One B-rep face of a CAD part: STEP entity #451.
In plain terms, the planar face has unit normal (1, 0, 0).
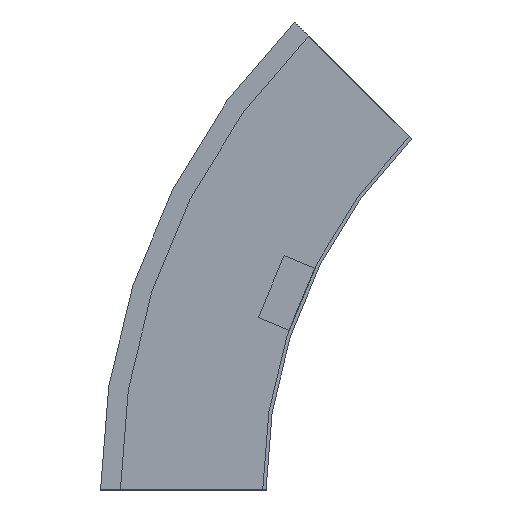
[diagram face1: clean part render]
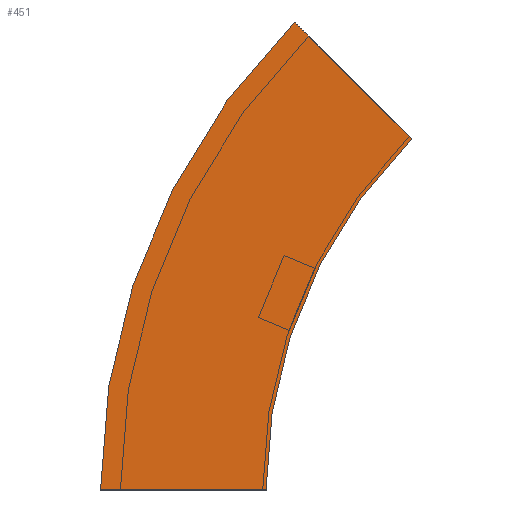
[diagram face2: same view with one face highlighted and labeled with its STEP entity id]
Its self-contained STEP definition (entity closure, numbers rounded to 3 decimals):
#3 = DIRECTION ( 'NONE',  ( 0., 0.707, 0.707 ) ) ;
#33 = CARTESIAN_POINT ( 'NONE',  ( 0., 100., 0. ) ) ;
#54 = LINE ( 'NONE', #233, #294 ) ;
#59 = ORIENTED_EDGE ( 'NONE', *, *, #468, .F. ) ;
#76 = AXIS2_PLACEMENT_3D ( 'NONE', #216, #171, #168 ) ;
#104 = ORIENTED_EDGE ( 'NONE', *, *, #415, .T. ) ;
#110 = AXIS2_PLACEMENT_3D ( 'NONE', #204, #162, #329 ) ;
#139 = CARTESIAN_POINT ( 'NONE',  ( 0., 0., 0. ) ) ;
#147 = CARTESIAN_POINT ( 'NONE',  ( 0., -17.157, 282.843 ) ) ;
#162 = DIRECTION ( 'NONE',  ( 1., 0., 0. ) ) ;
#168 = DIRECTION ( 'NONE',  ( 0., 1., 0. ) ) ;
#171 = DIRECTION ( 'NONE',  ( 1., 0., 0. ) ) ;
#172 = EDGE_CURVE ( 'NONE', #254, #179, #382, .T. ) ;
#179 = VERTEX_POINT ( 'NONE', #381 ) ;
#204 = CARTESIAN_POINT ( 'NONE',  ( 0., -300., 0. ) ) ;
#216 = CARTESIAN_POINT ( 'NONE',  ( 0., -300., 0. ) ) ;
#224 = EDGE_CURVE ( 'NONE', #254, #391, #256, .T. ) ;
#228 = CARTESIAN_POINT ( 'NONE',  ( 0., 0., 0. ) ) ;
#230 = DIRECTION ( 'NONE',  ( 0., 0., -1. ) ) ;
#233 = CARTESIAN_POINT ( 'NONE',  ( 0., -87.868, 212.132 ) ) ;
#254 = VERTEX_POINT ( 'NONE', #228 ) ;
#256 = LINE ( 'NONE', #514, #419 ) ;
#265 = VERTEX_POINT ( 'NONE', #147 ) ;
#277 = CIRCLE ( 'NONE', #110, 400. ) ;
#278 = ORIENTED_EDGE ( 'NONE', *, *, #224, .T. ) ;
#287 = AXIS2_PLACEMENT_3D ( 'NONE', #139, #521, #230 ) ;
#294 = VECTOR ( 'NONE', #3, 1000. ) ;
#329 = DIRECTION ( 'NONE',  ( 0., 1., 0. ) ) ;
#381 = CARTESIAN_POINT ( 'NONE',  ( 0., -87.868, 212.132 ) ) ;
#382 = CIRCLE ( 'NONE', #76, 300. ) ;
#391 = VERTEX_POINT ( 'NONE', #33 ) ;
#415 = EDGE_CURVE ( 'NONE', #391, #265, #277, .T. ) ;
#419 = VECTOR ( 'NONE', #516, 1000. ) ;
#423 = PLANE ( 'NONE',  #287 ) ;
#451 = ADVANCED_FACE ( 'NONE', ( #488 ), #423, .T. ) ;
#467 = ORIENTED_EDGE ( 'NONE', *, *, #172, .F. ) ;
#468 = EDGE_CURVE ( 'NONE', #179, #265, #54, .T. ) ;
#488 = FACE_OUTER_BOUND ( 'NONE', #531, .T. ) ;
#514 = CARTESIAN_POINT ( 'NONE',  ( 0., 0., 0. ) ) ;
#516 = DIRECTION ( 'NONE',  ( 0., 1., 0. ) ) ;
#521 = DIRECTION ( 'NONE',  ( 1., 0., 0. ) ) ;
#531 = EDGE_LOOP ( 'NONE', ( #104, #59, #467, #278 ) ) ;
